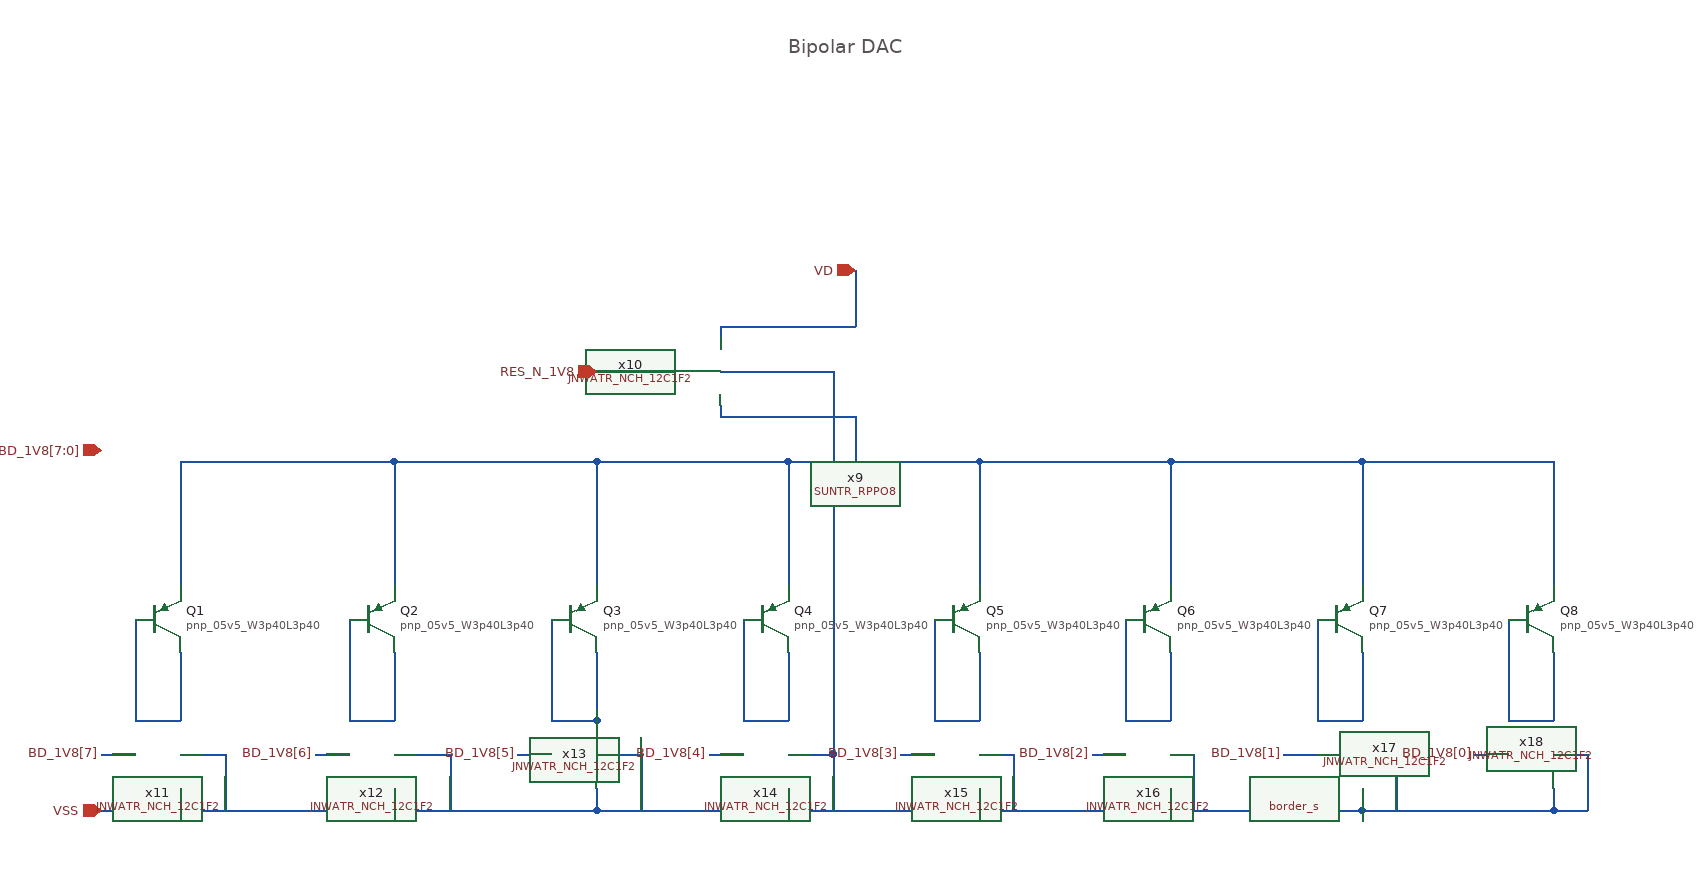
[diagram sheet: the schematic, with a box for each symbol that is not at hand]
v {xschem version=3.4.5 file_version=1.2
}
G {}
K {}
V {}
S {}
E {}
T {Bipolar DAC} 770 -810 0 0 0.5 0.5 {}
N 230 -260 230 -200 {
lab=#net1}
N 190 -290 190 -200 {
lab=#net1}
N 190 -120 230 -120 {
lab=VSS}
N 230 -120 420 -120 {
lab=VSS}
N 420 -260 420 -200 {
lab=#net2}
N 420 -120 600 -120 {
lab=VSS}
N 600 -260 600 -200 {
lab=#net3}
N 600 -120 770 -120 {
lab=VSS}
N 770 -260 770 -200 {
lab=#net4}
N 730 -290 730 -200 {
lab=#net4}
N 560 -290 560 -200 {
lab=#net3}
N 380 -290 380 -200 {
lab=#net2}
N 770 -120 940 -120 {
lab=VSS}
N 940 -260 940 -200 {
lab=#net5}
N 900 -290 900 -200 {
lab=#net5}
N 940 -120 1110 -120 {
lab=VSS}
N 1110 -260 1110 -200 {
lab=#net6}
N 1070 -290 1070 -200 {
lab=#net6}
N 1110 -120 1280 -120 {
lab=VSS}
N 1280 -260 1280 -200 {
lab=#net7}
N 1240 -290 1240 -200 {
lab=#net7}
N 1280 -120 1450 -120 {
lab=VSS}
N 1450 -260 1450 -200 {
lab=#net8}
N 1410 -290 1410 -200 {
lab=#net8}
N 1450 -340 1450 -320 {
lab=#net9}
N 1280 -340 1280 -320 {
lab=#net10}
N 1110 -340 1110 -320 {
lab=#net11}
N 940 -340 940 -320 {
lab=#net12}
N 770 -340 770 -320 {
lab=#net13}
N 600 -340 600 -320 {
lab=#net14}
N 420 -340 420 -320 {
lab=#net15}
N 230 -340 230 -320 {
lab=#net16}
N 1450 -120 1480 -120 {
lab=VSS}
N 230 -430 230 -400 {
lab=#net25}
N 230 -430 420 -430 {
lab=#net25}
N 420 -430 420 -400 {
lab=#net25}
N 420 -430 600 -430 {
lab=#net25}
N 600 -430 600 -410 {
lab=#net25}
N 770 -430 770 -400 {
lab=#net25}
N 600 -430 770 -430 {
lab=#net25}
N 940 -430 940 -400 {
lab=#net25}
N 770 -430 940 -430 {
lab=#net25}
N 1110 -430 1110 -400 {
lab=#net25}
N 940 -430 1110 -430 {
lab=#net25}
N 1280 -430 1280 -400 {
lab=#net25}
N 1110 -430 1280 -430 {
lab=#net25}
N 1450 -430 1450 -400 {
lab=#net25}
N 1280 -430 1450 -430 {
lab=#net25}
N 160 -120 190 -120 {
lab=VSS}
N 830 -470 830 -430 {
lab=#net25}
N 830 -600 830 -550 {
lab=VD}
N 710 -550 710 -540 {
lab=VD}
N 710 -550 830 -550 {
lab=VD}
N 710 -480 710 -470 {
lab=#net25}
N 710 -470 830 -470 {
lab=#net25}
N 710 -510 810 -510 {
lab=#net20}
N 590 -510 670 -510 {
lab=RES_N_1V8}
N 190 -200 230 -200 {
lab=#net1}
N 380 -200 420 -200 {
lab=#net2}
N 560 -200 600 -200 {
lab=#net3}
N 730 -200 770 -200 {
lab=#net4}
N 900 -200 940 -200 {
lab=#net5}
N 1070 -200 1110 -200 {
lab=#net6}
N 1240 -200 1280 -200 {
lab=#net7}
N 1410 -200 1450 -200 {
lab=#net8}
N 230 -170 270 -170 {
lab=#net26}
N 420 -170 470 -170 {
lab=#net27}
N 600 -170 640 -170 {
lab=#net28}
N 770 -170 810 -170 {
lab=#net29}
N 940 -170 970 -170 {
lab=#net30}
N 1110 -170 1130 -170 {
lab=#net31}
N 1280 -170 1310 -170 {
lab=#net32}
N 1450 -170 1480 -170 {
lab=#net33}
N 600 -210 600 -200 {
lab=#net3}
N 160 -170 190 -170 {
lab=BD_1V8[7]}
N 350 -170 380 -170 {
lab=BD_1V8[6]}
N 530 -170 560 -170 {
lab=BD_1V8[5]}
N 700 -170 730 -170 {
lab=BD_1V8[4]}
N 870 -170 900 -170 {
lab=BD_1V8[3]}
N 1040 -170 1070 -170 {
lab=BD_1V8[2]}
N 1210 -170 1240 -170 {
lab=BD_1V8[1]}
N 1380 -170 1410 -170 {
lab=BD_1V8[0]}
N 230 -400 230 -340 {}
N 420 -400 420 -340 {}
N 600 -410 600 -340 {}
N 770 -400 770 -340 {}
N 940 -400 940 -340 {}
N 1110 -400 1110 -340 {}
N 1280 -400 1280 -340 {}
N 1450 -400 1450 -340 {}
N 810 -510 810 -170 {}
N 810 -170 810 -120 {}
N 270 -170 270 -120 {}
N 230 -140 230 -120 {}
N 420 -140 420 -120 {}
N 470 -170 470 -120 {}
N 600 -140 600 -120 {}
N 640 -170 640 -120 {}
N 770 -140 770 -120 {}
N 940 -140 940 -120 {}
N 1110 -140 1110 -120 {}
N 1280 -140 1280 -120 {}
N 1450 -140 1450 -120 {}
N 1480 -170 1480 -120 {}
N 1310 -170 1310 -120 {}
N 1130 -170 1130 -120 {}
N 970 -170 970 -120 {}
C {sky130_fd_pr/pnp_05v5.sym} 210 -290 0 0 {name=Q1
model=pnp_05v5_W3p40L3p40
spiceprefix=X
}
C {sky130_fd_pr/pnp_05v5.sym} 400 -290 0 0 {name=Q2
model=pnp_05v5_W3p40L3p40
spiceprefix=X
}
C {sky130_fd_pr/pnp_05v5.sym} 580 -290 0 0 {name=Q3
model=pnp_05v5_W3p40L3p40
spiceprefix=X
}
C {sky130_fd_pr/pnp_05v5.sym} 750 -290 0 0 {name=Q4
model=pnp_05v5_W3p40L3p40
spiceprefix=X
}
C {sky130_fd_pr/pnp_05v5.sym} 920 -290 0 0 {name=Q5
model=pnp_05v5_W3p40L3p40
spiceprefix=X
}
C {sky130_fd_pr/pnp_05v5.sym} 1090 -290 0 0 {name=Q6
model=pnp_05v5_W3p40L3p40
spiceprefix=X
}
C {sky130_fd_pr/pnp_05v5.sym} 1260 -290 0 0 {name=Q7
model=pnp_05v5_W3p40L3p40
spiceprefix=X
}
C {sky130_fd_pr/pnp_05v5.sym} 1430 -290 0 0 {name=Q8
model=pnp_05v5_W3p40L3p40
spiceprefix=X
}
C {devices/ipin.sym} 160 -120 0 0 {name=p1 lab=VSS}
C {devices/iopin.sym} 830 -600 3 0 {name=p2 lab=VD}
C {devices/ipin.sym} 160 -440 0 0 {name=p3 lab=BD_1V8[7:0]}
C {cborder/border_s.sym} 1250 -170 0 0 {
user="Carsten Wulff"
company="Carsten Wulff Software"}
C {SUN_TR_SKY130NM/SUNTR_RPPO8.sym} 830 -550 1 0 {name=x9 }
C {JNW_ATR_SKY130NM/JNWATR_NCH_12C1F2.sym} 670 -510 0 0 {name=x10 }
C {devices/ipin.sym} 600 -510 0 0 {name=p12 lab=RES_N_1V8}
C {JNW_ATR_SKY130NM/JNWATR_NCH_12C1F2.sym} 190 -170 0 0 {name=x11 }
C {JNW_ATR_SKY130NM/JNWATR_NCH_12C1F2.sym} 380 -170 0 0 {name=x12 }
C {JNW_ATR_SKY130NM/JNWATR_NCH_12C1F2.sym} 560 -170 0 0 {name=x13 }
C {JNW_ATR_SKY130NM/JNWATR_NCH_12C1F2.sym} 730 -170 0 0 {name=x14 }
C {JNW_ATR_SKY130NM/JNWATR_NCH_12C1F2.sym} 900 -170 0 0 {name=x15 }
C {JNW_ATR_SKY130NM/JNWATR_NCH_12C1F2.sym} 1070 -170 0 0 {name=x16 }
C {JNW_ATR_SKY130NM/JNWATR_NCH_12C1F2.sym} 1240 -170 0 0 {name=x17 }
C {JNW_ATR_SKY130NM/JNWATR_NCH_12C1F2.sym} 1410 -170 0 0 {name=x18 }
C {devices/lab_wire.sym} 160 -170 0 0 {name=p13 sig_type=std_logic lab=BD_1V8[7]}
C {devices/lab_wire.sym} 350 -170 0 0 {name=p14 sig_type=std_logic lab=BD_1V8[6]}
C {devices/lab_wire.sym} 530 -170 0 0 {name=p15 sig_type=std_logic lab=BD_1V8[5]}
C {devices/lab_wire.sym} 700 -170 0 0 {name=p16 sig_type=std_logic lab=BD_1V8[4]}
C {devices/lab_wire.sym} 870 -170 0 0 {name=p17 sig_type=std_logic lab=BD_1V8[3]}
C {devices/lab_wire.sym} 1040 -170 0 0 {name=p18 sig_type=std_logic lab=BD_1V8[2]}
C {devices/lab_wire.sym} 1210 -170 0 0 {name=p19 sig_type=std_logic lab=BD_1V8[1]}
C {devices/lab_wire.sym} 1380 -170 0 0 {name=p20 sig_type=std_logic lab=BD_1V8[0]}
